VERSION 5.7 ;
  NOWIREEXTENSIONATPIN ON ;
  DIVIDERCHAR "/" ;
  BUSBITCHARS "[]" ;
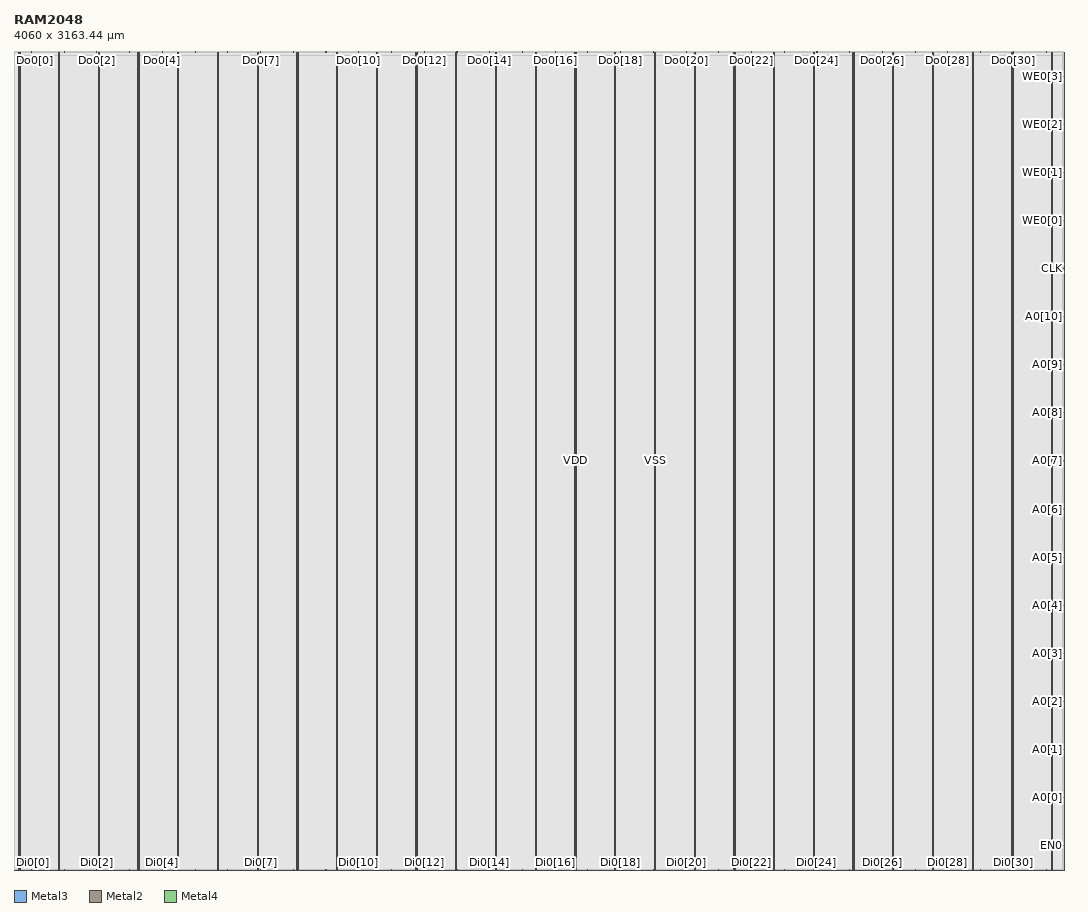
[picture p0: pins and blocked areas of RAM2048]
MACRO RAM2048
  CLASS BLOCK ;
  FOREIGN RAM2048 ;
  ORIGIN 0.000 0.000 ;
  SIZE 4060.000 BY 3163.440 ;
  PIN A0[0]
    DIRECTION INPUT ;
    USE SIGNAL ;
    ANTENNAGATEAREA 0.726000 ;
    PORT
      LAYER Metal3 ;
        RECT 4058.000 280.000 4060.000 280.560 ;
    END
  END A0[0]
  PIN A0[10]
    DIRECTION INPUT ;
    USE SIGNAL ;
    ANTENNAGATEAREA 0.726000 ;
    PORT
      LAYER Metal3 ;
        RECT 4058.000 2139.200 4060.000 2139.760 ;
    END
  END A0[10]
  PIN A0[1]
    DIRECTION INPUT ;
    USE SIGNAL ;
    ANTENNAGATEAREA 0.726000 ;
    PORT
      LAYER Metal3 ;
        RECT 4058.000 465.920 4060.000 466.480 ;
    END
  END A0[1]
  PIN A0[2]
    DIRECTION INPUT ;
    USE SIGNAL ;
    ANTENNAGATEAREA 0.726000 ;
    PORT
      LAYER Metal3 ;
        RECT 4058.000 651.840 4060.000 652.400 ;
    END
  END A0[2]
  PIN A0[3]
    DIRECTION INPUT ;
    USE SIGNAL ;
    ANTENNAGATEAREA 0.726000 ;
    PORT
      LAYER Metal3 ;
        RECT 4058.000 837.760 4060.000 838.320 ;
    END
  END A0[3]
  PIN A0[4]
    DIRECTION INPUT ;
    USE SIGNAL ;
    ANTENNAGATEAREA 0.726000 ;
    PORT
      LAYER Metal3 ;
        RECT 4058.000 1023.680 4060.000 1024.240 ;
    END
  END A0[4]
  PIN A0[5]
    DIRECTION INPUT ;
    USE SIGNAL ;
    ANTENNAGATEAREA 0.726000 ;
    PORT
      LAYER Metal3 ;
        RECT 4058.000 1209.600 4060.000 1210.160 ;
    END
  END A0[5]
  PIN A0[6]
    DIRECTION INPUT ;
    USE SIGNAL ;
    ANTENNAGATEAREA 0.726000 ;
    PORT
      LAYER Metal3 ;
        RECT 4058.000 1395.520 4060.000 1396.080 ;
    END
  END A0[6]
  PIN A0[7]
    DIRECTION INPUT ;
    USE SIGNAL ;
    ANTENNAGATEAREA 0.726000 ;
    PORT
      LAYER Metal3 ;
        RECT 4058.000 1581.440 4060.000 1582.000 ;
    END
  END A0[7]
  PIN A0[8]
    DIRECTION INPUT ;
    USE SIGNAL ;
    ANTENNAGATEAREA 0.726000 ;
    PORT
      LAYER Metal3 ;
        RECT 4058.000 1767.360 4060.000 1767.920 ;
    END
  END A0[8]
  PIN A0[9]
    DIRECTION INPUT ;
    USE SIGNAL ;
    ANTENNAGATEAREA 0.726000 ;
    PORT
      LAYER Metal3 ;
        RECT 4058.000 1953.280 4060.000 1953.840 ;
    END
  END A0[9]
  PIN CLK
    DIRECTION INPUT ;
    USE SIGNAL ;
    ANTENNAGATEAREA 1.183000 ;
    PORT
      LAYER Metal3 ;
        RECT 4058.000 2325.120 4060.000 2325.680 ;
    END
  END CLK
  PIN Di0[0]
    DIRECTION INPUT ;
    USE SIGNAL ;
    ANTENNAGATEAREA 4.738000 ;
    PORT
      LAYER Metal2 ;
        RECT 67.200 0.000 67.760 2.000 ;
    END
  END Di0[0]
  PIN Di0[10]
    DIRECTION INPUT ;
    USE SIGNAL ;
    ANTENNAGATEAREA 4.738000 ;
    PORT
      LAYER Metal2 ;
        RECT 1332.800 0.000 1333.360 2.000 ;
    END
  END Di0[10]
  PIN Di0[11]
    DIRECTION INPUT ;
    USE SIGNAL ;
    ANTENNAGATEAREA 4.738000 ;
    PORT
      LAYER Metal2 ;
        RECT 1459.360 0.000 1459.920 2.000 ;
    END
  END Di0[11]
  PIN Di0[12]
    DIRECTION INPUT ;
    USE SIGNAL ;
    ANTENNAGATEAREA 4.738000 ;
    PORT
      LAYER Metal2 ;
        RECT 1585.920 0.000 1586.480 2.000 ;
    END
  END Di0[12]
  PIN Di0[13]
    DIRECTION INPUT ;
    USE SIGNAL ;
    ANTENNAGATEAREA 4.738000 ;
    PORT
      LAYER Metal2 ;
        RECT 1712.480 0.000 1713.040 2.000 ;
    END
  END Di0[13]
  PIN Di0[14]
    DIRECTION INPUT ;
    USE SIGNAL ;
    ANTENNAGATEAREA 4.738000 ;
    PORT
      LAYER Metal2 ;
        RECT 1839.040 0.000 1839.600 2.000 ;
    END
  END Di0[14]
  PIN Di0[15]
    DIRECTION INPUT ;
    USE SIGNAL ;
    ANTENNAGATEAREA 4.738000 ;
    PORT
      LAYER Metal2 ;
        RECT 1965.600 0.000 1966.160 2.000 ;
    END
  END Di0[15]
  PIN Di0[16]
    DIRECTION INPUT ;
    USE SIGNAL ;
    ANTENNAGATEAREA 4.738000 ;
    PORT
      LAYER Metal2 ;
        RECT 2092.160 0.000 2092.720 2.000 ;
    END
  END Di0[16]
  PIN Di0[17]
    DIRECTION INPUT ;
    USE SIGNAL ;
    ANTENNAGATEAREA 4.738000 ;
    PORT
      LAYER Metal2 ;
        RECT 2218.720 0.000 2219.280 2.000 ;
    END
  END Di0[17]
  PIN Di0[18]
    DIRECTION INPUT ;
    USE SIGNAL ;
    ANTENNAGATEAREA 4.738000 ;
    PORT
      LAYER Metal2 ;
        RECT 2345.280 0.000 2345.840 2.000 ;
    END
  END Di0[18]
  PIN Di0[19]
    DIRECTION INPUT ;
    USE SIGNAL ;
    ANTENNAGATEAREA 4.738000 ;
    PORT
      LAYER Metal2 ;
        RECT 2471.840 0.000 2472.400 2.000 ;
    END
  END Di0[19]
  PIN Di0[1]
    DIRECTION INPUT ;
    USE SIGNAL ;
    ANTENNAGATEAREA 4.738000 ;
    PORT
      LAYER Metal2 ;
        RECT 193.760 0.000 194.320 2.000 ;
    END
  END Di0[1]
  PIN Di0[20]
    DIRECTION INPUT ;
    USE SIGNAL ;
    ANTENNAGATEAREA 4.738000 ;
    PORT
      LAYER Metal2 ;
        RECT 2598.400 0.000 2598.960 2.000 ;
    END
  END Di0[20]
  PIN Di0[21]
    DIRECTION INPUT ;
    USE SIGNAL ;
    ANTENNAGATEAREA 4.738000 ;
    PORT
      LAYER Metal2 ;
        RECT 2724.960 0.000 2725.520 2.000 ;
    END
  END Di0[21]
  PIN Di0[22]
    DIRECTION INPUT ;
    USE SIGNAL ;
    ANTENNAGATEAREA 4.738000 ;
    PORT
      LAYER Metal2 ;
        RECT 2851.520 0.000 2852.080 2.000 ;
    END
  END Di0[22]
  PIN Di0[23]
    DIRECTION INPUT ;
    USE SIGNAL ;
    ANTENNAGATEAREA 4.738000 ;
    PORT
      LAYER Metal2 ;
        RECT 2978.080 0.000 2978.640 2.000 ;
    END
  END Di0[23]
  PIN Di0[24]
    DIRECTION INPUT ;
    USE SIGNAL ;
    ANTENNAGATEAREA 4.738000 ;
    PORT
      LAYER Metal2 ;
        RECT 3104.640 0.000 3105.200 2.000 ;
    END
  END Di0[24]
  PIN Di0[25]
    DIRECTION INPUT ;
    USE SIGNAL ;
    ANTENNAGATEAREA 4.738000 ;
    PORT
      LAYER Metal2 ;
        RECT 3231.200 0.000 3231.760 2.000 ;
    END
  END Di0[25]
  PIN Di0[26]
    DIRECTION INPUT ;
    USE SIGNAL ;
    ANTENNAGATEAREA 4.738000 ;
    PORT
      LAYER Metal2 ;
        RECT 3357.760 0.000 3358.320 2.000 ;
    END
  END Di0[26]
  PIN Di0[27]
    DIRECTION INPUT ;
    USE SIGNAL ;
    ANTENNAGATEAREA 4.738000 ;
    PORT
      LAYER Metal2 ;
        RECT 3484.320 0.000 3484.880 2.000 ;
    END
  END Di0[27]
  PIN Di0[28]
    DIRECTION INPUT ;
    USE SIGNAL ;
    ANTENNAGATEAREA 4.738000 ;
    PORT
      LAYER Metal2 ;
        RECT 3610.880 0.000 3611.440 2.000 ;
    END
  END Di0[28]
  PIN Di0[29]
    DIRECTION INPUT ;
    USE SIGNAL ;
    ANTENNAGATEAREA 4.738000 ;
    PORT
      LAYER Metal2 ;
        RECT 3737.440 0.000 3738.000 2.000 ;
    END
  END Di0[29]
  PIN Di0[2]
    DIRECTION INPUT ;
    USE SIGNAL ;
    ANTENNAGATEAREA 4.738000 ;
    PORT
      LAYER Metal2 ;
        RECT 320.320 0.000 320.880 2.000 ;
    END
  END Di0[2]
  PIN Di0[30]
    DIRECTION INPUT ;
    USE SIGNAL ;
    ANTENNAGATEAREA 4.738000 ;
    PORT
      LAYER Metal2 ;
        RECT 3864.000 0.000 3864.560 2.000 ;
    END
  END Di0[30]
  PIN Di0[31]
    DIRECTION INPUT ;
    USE SIGNAL ;
    ANTENNAGATEAREA 4.738000 ;
    PORT
      LAYER Metal2 ;
        RECT 3990.560 0.000 3991.120 2.000 ;
    END
  END Di0[31]
  PIN Di0[3]
    DIRECTION INPUT ;
    USE SIGNAL ;
    ANTENNAGATEAREA 4.738000 ;
    PORT
      LAYER Metal2 ;
        RECT 446.880 0.000 447.440 2.000 ;
    END
  END Di0[3]
  PIN Di0[4]
    DIRECTION INPUT ;
    USE SIGNAL ;
    ANTENNAGATEAREA 4.738000 ;
    PORT
      LAYER Metal2 ;
        RECT 573.440 0.000 574.000 2.000 ;
    END
  END Di0[4]
  PIN Di0[5]
    DIRECTION INPUT ;
    USE SIGNAL ;
    ANTENNAGATEAREA 4.738000 ;
    PORT
      LAYER Metal2 ;
        RECT 700.000 0.000 700.560 2.000 ;
    END
  END Di0[5]
  PIN Di0[6]
    DIRECTION INPUT ;
    USE SIGNAL ;
    ANTENNAGATEAREA 4.738000 ;
    PORT
      LAYER Metal2 ;
        RECT 826.560 0.000 827.120 2.000 ;
    END
  END Di0[6]
  PIN Di0[7]
    DIRECTION INPUT ;
    USE SIGNAL ;
    ANTENNAGATEAREA 4.738000 ;
    PORT
      LAYER Metal2 ;
        RECT 953.120 0.000 953.680 2.000 ;
    END
  END Di0[7]
  PIN Di0[8]
    DIRECTION INPUT ;
    USE SIGNAL ;
    ANTENNAGATEAREA 4.738000 ;
    PORT
      LAYER Metal2 ;
        RECT 1079.680 0.000 1080.240 2.000 ;
    END
  END Di0[8]
  PIN Di0[9]
    DIRECTION INPUT ;
    USE SIGNAL ;
    ANTENNAGATEAREA 4.738000 ;
    PORT
      LAYER Metal2 ;
        RECT 1206.240 0.000 1206.800 2.000 ;
    END
  END Di0[9]
  PIN Do0[0]
    DIRECTION OUTPUT ;
    USE SIGNAL ;
    ANTENNADIFFAREA 0.510400 ;
    PORT
      LAYER Metal2 ;
        RECT 67.200 3161.440 67.760 3163.440 ;
    END
  END Do0[0]
  PIN Do0[10]
    DIRECTION OUTPUT ;
    USE SIGNAL ;
    ANTENNADIFFAREA 0.510400 ;
    PORT
      LAYER Metal2 ;
        RECT 1332.800 3161.440 1333.360 3163.440 ;
    END
  END Do0[10]
  PIN Do0[11]
    DIRECTION OUTPUT ;
    USE SIGNAL ;
    ANTENNADIFFAREA 0.510400 ;
    PORT
      LAYER Metal2 ;
        RECT 1459.360 3161.440 1459.920 3163.440 ;
    END
  END Do0[11]
  PIN Do0[12]
    DIRECTION OUTPUT ;
    USE SIGNAL ;
    ANTENNADIFFAREA 0.510400 ;
    PORT
      LAYER Metal2 ;
        RECT 1585.920 3161.440 1586.480 3163.440 ;
    END
  END Do0[12]
  PIN Do0[13]
    DIRECTION OUTPUT ;
    USE SIGNAL ;
    ANTENNADIFFAREA 0.510400 ;
    PORT
      LAYER Metal2 ;
        RECT 1712.480 3161.440 1713.040 3163.440 ;
    END
  END Do0[13]
  PIN Do0[14]
    DIRECTION OUTPUT ;
    USE SIGNAL ;
    ANTENNADIFFAREA 0.510400 ;
    PORT
      LAYER Metal2 ;
        RECT 1839.040 3161.440 1839.600 3163.440 ;
    END
  END Do0[14]
  PIN Do0[15]
    DIRECTION OUTPUT ;
    USE SIGNAL ;
    ANTENNADIFFAREA 0.510400 ;
    PORT
      LAYER Metal2 ;
        RECT 1965.600 3161.440 1966.160 3163.440 ;
    END
  END Do0[15]
  PIN Do0[16]
    DIRECTION OUTPUT ;
    USE SIGNAL ;
    ANTENNADIFFAREA 0.510400 ;
    PORT
      LAYER Metal2 ;
        RECT 2092.160 3161.440 2092.720 3163.440 ;
    END
  END Do0[16]
  PIN Do0[17]
    DIRECTION OUTPUT ;
    USE SIGNAL ;
    ANTENNADIFFAREA 0.510400 ;
    PORT
      LAYER Metal2 ;
        RECT 2218.720 3161.440 2219.280 3163.440 ;
    END
  END Do0[17]
  PIN Do0[18]
    DIRECTION OUTPUT ;
    USE SIGNAL ;
    ANTENNADIFFAREA 0.510400 ;
    PORT
      LAYER Metal2 ;
        RECT 2345.280 3161.440 2345.840 3163.440 ;
    END
  END Do0[18]
  PIN Do0[19]
    DIRECTION OUTPUT ;
    USE SIGNAL ;
    ANTENNADIFFAREA 0.510400 ;
    PORT
      LAYER Metal2 ;
        RECT 2471.840 3161.440 2472.400 3163.440 ;
    END
  END Do0[19]
  PIN Do0[1]
    DIRECTION OUTPUT ;
    USE SIGNAL ;
    ANTENNADIFFAREA 0.510400 ;
    PORT
      LAYER Metal2 ;
        RECT 193.760 3161.440 194.320 3163.440 ;
    END
  END Do0[1]
  PIN Do0[20]
    DIRECTION OUTPUT ;
    USE SIGNAL ;
    ANTENNADIFFAREA 0.510400 ;
    PORT
      LAYER Metal2 ;
        RECT 2598.400 3161.440 2598.960 3163.440 ;
    END
  END Do0[20]
  PIN Do0[21]
    DIRECTION OUTPUT ;
    USE SIGNAL ;
    ANTENNADIFFAREA 0.510400 ;
    PORT
      LAYER Metal2 ;
        RECT 2724.960 3161.440 2725.520 3163.440 ;
    END
  END Do0[21]
  PIN Do0[22]
    DIRECTION OUTPUT ;
    USE SIGNAL ;
    ANTENNADIFFAREA 0.510400 ;
    PORT
      LAYER Metal2 ;
        RECT 2851.520 3161.440 2852.080 3163.440 ;
    END
  END Do0[22]
  PIN Do0[23]
    DIRECTION OUTPUT ;
    USE SIGNAL ;
    ANTENNADIFFAREA 0.510400 ;
    PORT
      LAYER Metal2 ;
        RECT 2978.080 3161.440 2978.640 3163.440 ;
    END
  END Do0[23]
  PIN Do0[24]
    DIRECTION OUTPUT ;
    USE SIGNAL ;
    ANTENNADIFFAREA 0.510400 ;
    PORT
      LAYER Metal2 ;
        RECT 3104.640 3161.440 3105.200 3163.440 ;
    END
  END Do0[24]
  PIN Do0[25]
    DIRECTION OUTPUT ;
    USE SIGNAL ;
    ANTENNADIFFAREA 0.510400 ;
    PORT
      LAYER Metal2 ;
        RECT 3231.200 3161.440 3231.760 3163.440 ;
    END
  END Do0[25]
  PIN Do0[26]
    DIRECTION OUTPUT ;
    USE SIGNAL ;
    ANTENNADIFFAREA 0.510400 ;
    PORT
      LAYER Metal2 ;
        RECT 3357.760 3161.440 3358.320 3163.440 ;
    END
  END Do0[26]
  PIN Do0[27]
    DIRECTION OUTPUT ;
    USE SIGNAL ;
    ANTENNADIFFAREA 0.510400 ;
    PORT
      LAYER Metal2 ;
        RECT 3484.320 3161.440 3484.880 3163.440 ;
    END
  END Do0[27]
  PIN Do0[28]
    DIRECTION OUTPUT ;
    USE SIGNAL ;
    ANTENNADIFFAREA 0.510400 ;
    PORT
      LAYER Metal2 ;
        RECT 3610.880 3161.440 3611.440 3163.440 ;
    END
  END Do0[28]
  PIN Do0[29]
    DIRECTION OUTPUT ;
    USE SIGNAL ;
    ANTENNADIFFAREA 0.510400 ;
    PORT
      LAYER Metal2 ;
        RECT 3737.440 3161.440 3738.000 3163.440 ;
    END
  END Do0[29]
  PIN Do0[2]
    DIRECTION OUTPUT ;
    USE SIGNAL ;
    ANTENNADIFFAREA 0.510400 ;
    PORT
      LAYER Metal2 ;
        RECT 320.320 3161.440 320.880 3163.440 ;
    END
  END Do0[2]
  PIN Do0[30]
    DIRECTION OUTPUT ;
    USE SIGNAL ;
    ANTENNADIFFAREA 0.510400 ;
    PORT
      LAYER Metal2 ;
        RECT 3864.000 3161.440 3864.560 3163.440 ;
    END
  END Do0[30]
  PIN Do0[31]
    DIRECTION OUTPUT ;
    USE SIGNAL ;
    ANTENNADIFFAREA 0.510400 ;
    PORT
      LAYER Metal2 ;
        RECT 3990.560 3161.440 3991.120 3163.440 ;
    END
  END Do0[31]
  PIN Do0[3]
    DIRECTION OUTPUT ;
    USE SIGNAL ;
    ANTENNADIFFAREA 0.510400 ;
    PORT
      LAYER Metal2 ;
        RECT 446.880 3161.440 447.440 3163.440 ;
    END
  END Do0[3]
  PIN Do0[4]
    DIRECTION OUTPUT ;
    USE SIGNAL ;
    ANTENNADIFFAREA 0.510400 ;
    PORT
      LAYER Metal2 ;
        RECT 573.440 3161.440 574.000 3163.440 ;
    END
  END Do0[4]
  PIN Do0[5]
    DIRECTION OUTPUT ;
    USE SIGNAL ;
    ANTENNADIFFAREA 0.510400 ;
    PORT
      LAYER Metal2 ;
        RECT 700.000 3161.440 700.560 3163.440 ;
    END
  END Do0[5]
  PIN Do0[6]
    DIRECTION OUTPUT ;
    USE SIGNAL ;
    ANTENNADIFFAREA 0.510400 ;
    PORT
      LAYER Metal2 ;
        RECT 826.560 3161.440 827.120 3163.440 ;
    END
  END Do0[6]
  PIN Do0[7]
    DIRECTION OUTPUT ;
    USE SIGNAL ;
    ANTENNADIFFAREA 0.510400 ;
    PORT
      LAYER Metal2 ;
        RECT 953.120 3161.440 953.680 3163.440 ;
    END
  END Do0[7]
  PIN Do0[8]
    DIRECTION OUTPUT ;
    USE SIGNAL ;
    ANTENNADIFFAREA 0.510400 ;
    PORT
      LAYER Metal2 ;
        RECT 1079.680 3161.440 1080.240 3163.440 ;
    END
  END Do0[8]
  PIN Do0[9]
    DIRECTION OUTPUT ;
    USE SIGNAL ;
    ANTENNADIFFAREA 0.510400 ;
    PORT
      LAYER Metal2 ;
        RECT 1206.240 3161.440 1206.800 3163.440 ;
    END
  END Do0[9]
  PIN EN0
    DIRECTION INPUT ;
    USE SIGNAL ;
    ANTENNAGATEAREA 0.726000 ;
    PORT
      LAYER Metal3 ;
        RECT 4058.000 94.080 4060.000 94.640 ;
    END
  END EN0
  PIN VDD
    DIRECTION INOUT ;
    USE POWER ;
    PORT
      LAYER Metal4 ;
        RECT 18.320 3.620 19.920 3159.820 ;
    END
    PORT
      LAYER Metal4 ;
        RECT 171.920 3.620 173.520 3159.820 ;
    END
    PORT
      LAYER Metal4 ;
        RECT 325.520 3.620 327.120 3159.820 ;
    END
    PORT
      LAYER Metal4 ;
        RECT 479.120 3.620 480.720 3159.820 ;
    END
    PORT
      LAYER Metal4 ;
        RECT 632.720 3.620 634.320 3159.820 ;
    END
    PORT
      LAYER Metal4 ;
        RECT 786.320 3.620 787.920 3159.820 ;
    END
    PORT
      LAYER Metal4 ;
        RECT 939.920 3.620 941.520 3159.820 ;
    END
    PORT
      LAYER Metal4 ;
        RECT 1093.520 3.620 1095.120 3159.820 ;
    END
    PORT
      LAYER Metal4 ;
        RECT 1247.120 3.620 1248.720 3159.820 ;
    END
    PORT
      LAYER Metal4 ;
        RECT 1400.720 3.620 1402.320 3159.820 ;
    END
    PORT
      LAYER Metal4 ;
        RECT 1554.320 3.620 1555.920 3159.820 ;
    END
    PORT
      LAYER Metal4 ;
        RECT 1707.920 3.620 1709.520 3159.820 ;
    END
    PORT
      LAYER Metal4 ;
        RECT 1861.520 3.620 1863.120 3159.820 ;
    END
    PORT
      LAYER Metal4 ;
        RECT 2015.120 3.620 2016.720 3159.820 ;
    END
    PORT
      LAYER Metal4 ;
        RECT 2168.720 3.620 2170.320 3159.820 ;
    END
    PORT
      LAYER Metal4 ;
        RECT 2322.320 3.620 2323.920 3159.820 ;
    END
    PORT
      LAYER Metal4 ;
        RECT 2475.920 3.620 2477.520 3159.820 ;
    END
    PORT
      LAYER Metal4 ;
        RECT 2629.520 3.620 2631.120 3159.820 ;
    END
    PORT
      LAYER Metal4 ;
        RECT 2783.120 3.620 2784.720 3159.820 ;
    END
    PORT
      LAYER Metal4 ;
        RECT 2936.720 3.620 2938.320 3159.820 ;
    END
    PORT
      LAYER Metal4 ;
        RECT 3090.320 3.620 3091.920 3159.820 ;
    END
    PORT
      LAYER Metal4 ;
        RECT 3243.920 3.620 3245.520 3159.820 ;
    END
    PORT
      LAYER Metal4 ;
        RECT 3397.520 3.620 3399.120 3159.820 ;
    END
    PORT
      LAYER Metal4 ;
        RECT 3551.120 3.620 3552.720 3159.820 ;
    END
    PORT
      LAYER Metal4 ;
        RECT 3704.720 3.620 3706.320 3159.820 ;
    END
    PORT
      LAYER Metal4 ;
        RECT 3858.320 3.620 3859.920 3159.820 ;
    END
    PORT
      LAYER Metal4 ;
        RECT 4011.920 3.620 4013.520 3159.820 ;
    END
  END VDD
  PIN VSS
    DIRECTION INOUT ;
    USE GROUND ;
    PORT
      LAYER Metal4 ;
        RECT 21.620 3.620 23.220 3159.820 ;
    END
    PORT
      LAYER Metal4 ;
        RECT 175.220 3.620 176.820 3159.820 ;
    END
    PORT
      LAYER Metal4 ;
        RECT 328.820 3.620 330.420 3159.820 ;
    END
    PORT
      LAYER Metal4 ;
        RECT 482.420 3.620 484.020 3159.820 ;
    END
    PORT
      LAYER Metal4 ;
        RECT 636.020 3.620 637.620 3159.820 ;
    END
    PORT
      LAYER Metal4 ;
        RECT 789.620 3.620 791.220 3159.820 ;
    END
    PORT
      LAYER Metal4 ;
        RECT 943.220 3.620 944.820 3159.820 ;
    END
    PORT
      LAYER Metal4 ;
        RECT 1096.820 3.620 1098.420 3159.820 ;
    END
    PORT
      LAYER Metal4 ;
        RECT 1250.420 3.620 1252.020 3159.820 ;
    END
    PORT
      LAYER Metal4 ;
        RECT 1404.020 3.620 1405.620 3159.820 ;
    END
    PORT
      LAYER Metal4 ;
        RECT 1557.620 3.620 1559.220 3159.820 ;
    END
    PORT
      LAYER Metal4 ;
        RECT 1711.220 3.620 1712.820 3159.820 ;
    END
    PORT
      LAYER Metal4 ;
        RECT 1864.820 3.620 1866.420 3159.820 ;
    END
    PORT
      LAYER Metal4 ;
        RECT 2018.420 3.620 2020.020 3159.820 ;
    END
    PORT
      LAYER Metal4 ;
        RECT 2172.020 3.620 2173.620 3159.820 ;
    END
    PORT
      LAYER Metal4 ;
        RECT 2325.620 3.620 2327.220 3159.820 ;
    END
    PORT
      LAYER Metal4 ;
        RECT 2479.220 3.620 2480.820 3159.820 ;
    END
    PORT
      LAYER Metal4 ;
        RECT 2632.820 3.620 2634.420 3159.820 ;
    END
    PORT
      LAYER Metal4 ;
        RECT 2786.420 3.620 2788.020 3159.820 ;
    END
    PORT
      LAYER Metal4 ;
        RECT 2940.020 3.620 2941.620 3159.820 ;
    END
    PORT
      LAYER Metal4 ;
        RECT 3093.620 3.620 3095.220 3159.820 ;
    END
    PORT
      LAYER Metal4 ;
        RECT 3247.220 3.620 3248.820 3159.820 ;
    END
    PORT
      LAYER Metal4 ;
        RECT 3400.820 3.620 3402.420 3159.820 ;
    END
    PORT
      LAYER Metal4 ;
        RECT 3554.420 3.620 3556.020 3159.820 ;
    END
    PORT
      LAYER Metal4 ;
        RECT 3708.020 3.620 3709.620 3159.820 ;
    END
    PORT
      LAYER Metal4 ;
        RECT 3861.620 3.620 3863.220 3159.820 ;
    END
    PORT
      LAYER Metal4 ;
        RECT 4015.220 3.620 4016.820 3159.820 ;
    END
  END VSS
  PIN WE0[0]
    DIRECTION INPUT ;
    USE SIGNAL ;
    ANTENNAGATEAREA 0.726000 ;
    PORT
      LAYER Metal3 ;
        RECT 4058.000 2511.040 4060.000 2511.600 ;
    END
  END WE0[0]
  PIN WE0[1]
    DIRECTION INPUT ;
    USE SIGNAL ;
    ANTENNAGATEAREA 0.726000 ;
    PORT
      LAYER Metal3 ;
        RECT 4058.000 2696.960 4060.000 2697.520 ;
    END
  END WE0[1]
  PIN WE0[2]
    DIRECTION INPUT ;
    USE SIGNAL ;
    ANTENNAGATEAREA 0.726000 ;
    PORT
      LAYER Metal3 ;
        RECT 4058.000 2882.880 4060.000 2883.440 ;
    END
  END WE0[2]
  PIN WE0[3]
    DIRECTION INPUT ;
    USE SIGNAL ;
    ANTENNAGATEAREA 0.726000 ;
    PORT
      LAYER Metal3 ;
        RECT 4058.000 3068.800 4060.000 3069.360 ;
    END
  END WE0[3]
  OBS
      LAYER Nwell ;
        RECT 2.370 3.490 4057.630 3159.950 ;
      LAYER Metal1 ;
        RECT 2.800 3.620 4057.200 3159.820 ;
      LAYER Metal2 ;
        RECT 2.380 3161.140 66.900 3163.350 ;
        RECT 68.060 3161.140 193.460 3163.350 ;
        RECT 194.620 3161.140 320.020 3163.350 ;
        RECT 321.180 3161.140 446.580 3163.350 ;
        RECT 447.740 3161.140 573.140 3163.350 ;
        RECT 574.300 3161.140 699.700 3163.350 ;
        RECT 700.860 3161.140 826.260 3163.350 ;
        RECT 827.420 3161.140 952.820 3163.350 ;
        RECT 953.980 3161.140 1079.380 3163.350 ;
        RECT 1080.540 3161.140 1205.940 3163.350 ;
        RECT 1207.100 3161.140 1332.500 3163.350 ;
        RECT 1333.660 3161.140 1459.060 3163.350 ;
        RECT 1460.220 3161.140 1585.620 3163.350 ;
        RECT 1586.780 3161.140 1712.180 3163.350 ;
        RECT 1713.340 3161.140 1838.740 3163.350 ;
        RECT 1839.900 3161.140 1965.300 3163.350 ;
        RECT 1966.460 3161.140 2091.860 3163.350 ;
        RECT 2093.020 3161.140 2218.420 3163.350 ;
        RECT 2219.580 3161.140 2344.980 3163.350 ;
        RECT 2346.140 3161.140 2471.540 3163.350 ;
        RECT 2472.700 3161.140 2598.100 3163.350 ;
        RECT 2599.260 3161.140 2724.660 3163.350 ;
        RECT 2725.820 3161.140 2851.220 3163.350 ;
        RECT 2852.380 3161.140 2977.780 3163.350 ;
        RECT 2978.940 3161.140 3104.340 3163.350 ;
        RECT 3105.500 3161.140 3230.900 3163.350 ;
        RECT 3232.060 3161.140 3357.460 3163.350 ;
        RECT 3358.620 3161.140 3484.020 3163.350 ;
        RECT 3485.180 3161.140 3610.580 3163.350 ;
        RECT 3611.740 3161.140 3737.140 3163.350 ;
        RECT 3738.300 3161.140 3863.700 3163.350 ;
        RECT 3864.860 3161.140 3990.260 3163.350 ;
        RECT 3991.420 3161.140 4058.740 3163.350 ;
        RECT 2.380 2.300 4058.740 3161.140 ;
        RECT 2.380 0.090 66.900 2.300 ;
        RECT 68.060 0.090 193.460 2.300 ;
        RECT 194.620 0.090 320.020 2.300 ;
        RECT 321.180 0.090 446.580 2.300 ;
        RECT 447.740 0.090 573.140 2.300 ;
        RECT 574.300 0.090 699.700 2.300 ;
        RECT 700.860 0.090 826.260 2.300 ;
        RECT 827.420 0.090 952.820 2.300 ;
        RECT 953.980 0.090 1079.380 2.300 ;
        RECT 1080.540 0.090 1205.940 2.300 ;
        RECT 1207.100 0.090 1332.500 2.300 ;
        RECT 1333.660 0.090 1459.060 2.300 ;
        RECT 1460.220 0.090 1585.620 2.300 ;
        RECT 1586.780 0.090 1712.180 2.300 ;
        RECT 1713.340 0.090 1838.740 2.300 ;
        RECT 1839.900 0.090 1965.300 2.300 ;
        RECT 1966.460 0.090 2091.860 2.300 ;
        RECT 2093.020 0.090 2218.420 2.300 ;
        RECT 2219.580 0.090 2344.980 2.300 ;
        RECT 2346.140 0.090 2471.540 2.300 ;
        RECT 2472.700 0.090 2598.100 2.300 ;
        RECT 2599.260 0.090 2724.660 2.300 ;
        RECT 2725.820 0.090 2851.220 2.300 ;
        RECT 2852.380 0.090 2977.780 2.300 ;
        RECT 2978.940 0.090 3104.340 2.300 ;
        RECT 3105.500 0.090 3230.900 2.300 ;
        RECT 3232.060 0.090 3357.460 2.300 ;
        RECT 3358.620 0.090 3484.020 2.300 ;
        RECT 3485.180 0.090 3610.580 2.300 ;
        RECT 3611.740 0.090 3737.140 2.300 ;
        RECT 3738.300 0.090 3863.700 2.300 ;
        RECT 3864.860 0.090 3990.260 2.300 ;
        RECT 3991.420 0.090 4058.740 2.300 ;
      LAYER Metal3 ;
        RECT 2.330 3069.660 4058.790 3163.300 ;
        RECT 2.330 3068.500 4057.700 3069.660 ;
        RECT 2.330 2883.740 4058.790 3068.500 ;
        RECT 2.330 2882.580 4057.700 2883.740 ;
        RECT 2.330 2697.820 4058.790 2882.580 ;
        RECT 2.330 2696.660 4057.700 2697.820 ;
        RECT 2.330 2511.900 4058.790 2696.660 ;
        RECT 2.330 2510.740 4057.700 2511.900 ;
        RECT 2.330 2325.980 4058.790 2510.740 ;
        RECT 2.330 2324.820 4057.700 2325.980 ;
        RECT 2.330 2140.060 4058.790 2324.820 ;
        RECT 2.330 2138.900 4057.700 2140.060 ;
        RECT 2.330 1954.140 4058.790 2138.900 ;
        RECT 2.330 1952.980 4057.700 1954.140 ;
        RECT 2.330 1768.220 4058.790 1952.980 ;
        RECT 2.330 1767.060 4057.700 1768.220 ;
        RECT 2.330 1582.300 4058.790 1767.060 ;
        RECT 2.330 1581.140 4057.700 1582.300 ;
        RECT 2.330 1396.380 4058.790 1581.140 ;
        RECT 2.330 1395.220 4057.700 1396.380 ;
        RECT 2.330 1210.460 4058.790 1395.220 ;
        RECT 2.330 1209.300 4057.700 1210.460 ;
        RECT 2.330 1024.540 4058.790 1209.300 ;
        RECT 2.330 1023.380 4057.700 1024.540 ;
        RECT 2.330 838.620 4058.790 1023.380 ;
        RECT 2.330 837.460 4057.700 838.620 ;
        RECT 2.330 652.700 4058.790 837.460 ;
        RECT 2.330 651.540 4057.700 652.700 ;
        RECT 2.330 466.780 4058.790 651.540 ;
        RECT 2.330 465.620 4057.700 466.780 ;
        RECT 2.330 280.860 4058.790 465.620 ;
        RECT 2.330 279.700 4057.700 280.860 ;
        RECT 2.330 94.940 4058.790 279.700 ;
        RECT 2.330 93.780 4057.700 94.940 ;
        RECT 2.330 0.140 4058.790 93.780 ;
      LAYER Metal4 ;
        RECT 3.500 3160.120 4054.260 3161.670 ;
        RECT 3.500 3.320 18.020 3160.120 ;
        RECT 20.220 3.320 21.320 3160.120 ;
        RECT 23.520 3.320 171.620 3160.120 ;
        RECT 173.820 3.320 174.920 3160.120 ;
        RECT 177.120 3.320 325.220 3160.120 ;
        RECT 327.420 3.320 328.520 3160.120 ;
        RECT 330.720 3.320 478.820 3160.120 ;
        RECT 481.020 3.320 482.120 3160.120 ;
        RECT 484.320 3.320 632.420 3160.120 ;
        RECT 634.620 3.320 635.720 3160.120 ;
        RECT 637.920 3.320 786.020 3160.120 ;
        RECT 788.220 3.320 789.320 3160.120 ;
        RECT 791.520 3.320 939.620 3160.120 ;
        RECT 941.820 3.320 942.920 3160.120 ;
        RECT 945.120 3.320 1093.220 3160.120 ;
        RECT 1095.420 3.320 1096.520 3160.120 ;
        RECT 1098.720 3.320 1246.820 3160.120 ;
        RECT 1249.020 3.320 1250.120 3160.120 ;
        RECT 1252.320 3.320 1400.420 3160.120 ;
        RECT 1402.620 3.320 1403.720 3160.120 ;
        RECT 1405.920 3.320 1554.020 3160.120 ;
        RECT 1556.220 3.320 1557.320 3160.120 ;
        RECT 1559.520 3.320 1707.620 3160.120 ;
        RECT 1709.820 3.320 1710.920 3160.120 ;
        RECT 1713.120 3.320 1861.220 3160.120 ;
        RECT 1863.420 3.320 1864.520 3160.120 ;
        RECT 1866.720 3.320 2014.820 3160.120 ;
        RECT 2017.020 3.320 2018.120 3160.120 ;
        RECT 2020.320 3.320 2168.420 3160.120 ;
        RECT 2170.620 3.320 2171.720 3160.120 ;
        RECT 2173.920 3.320 2322.020 3160.120 ;
        RECT 2324.220 3.320 2325.320 3160.120 ;
        RECT 2327.520 3.320 2475.620 3160.120 ;
        RECT 2477.820 3.320 2478.920 3160.120 ;
        RECT 2481.120 3.320 2629.220 3160.120 ;
        RECT 2631.420 3.320 2632.520 3160.120 ;
        RECT 2634.720 3.320 2782.820 3160.120 ;
        RECT 2785.020 3.320 2786.120 3160.120 ;
        RECT 2788.320 3.320 2936.420 3160.120 ;
        RECT 2938.620 3.320 2939.720 3160.120 ;
        RECT 2941.920 3.320 3090.020 3160.120 ;
        RECT 3092.220 3.320 3093.320 3160.120 ;
        RECT 3095.520 3.320 3243.620 3160.120 ;
        RECT 3245.820 3.320 3246.920 3160.120 ;
        RECT 3249.120 3.320 3397.220 3160.120 ;
        RECT 3399.420 3.320 3400.520 3160.120 ;
        RECT 3402.720 3.320 3550.820 3160.120 ;
        RECT 3553.020 3.320 3554.120 3160.120 ;
        RECT 3556.320 3.320 3704.420 3160.120 ;
        RECT 3706.620 3.320 3707.720 3160.120 ;
        RECT 3709.920 3.320 3858.020 3160.120 ;
        RECT 3860.220 3.320 3861.320 3160.120 ;
        RECT 3863.520 3.320 4011.620 3160.120 ;
        RECT 4013.820 3.320 4014.920 3160.120 ;
        RECT 4017.120 3.320 4054.260 3160.120 ;
        RECT 3.500 0.090 4054.260 3.320 ;
      LAYER Metal5 ;
        RECT 3.420 2.030 4054.340 3149.770 ;
  END
END RAM2048
END LIBRARY

